One B-rep face of a CAD part: STEP entity #436.
In plain terms, the planar face has unit normal (1, 0, 0).
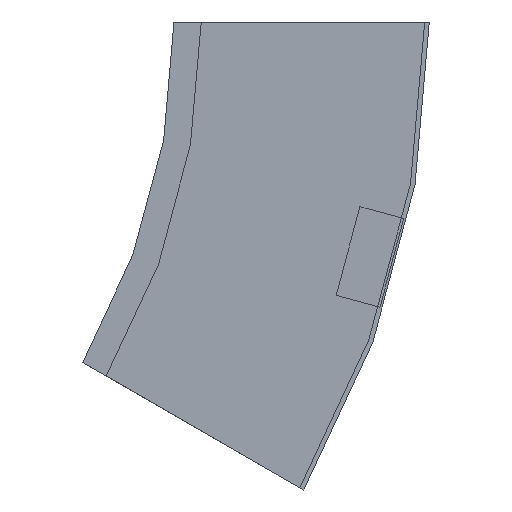
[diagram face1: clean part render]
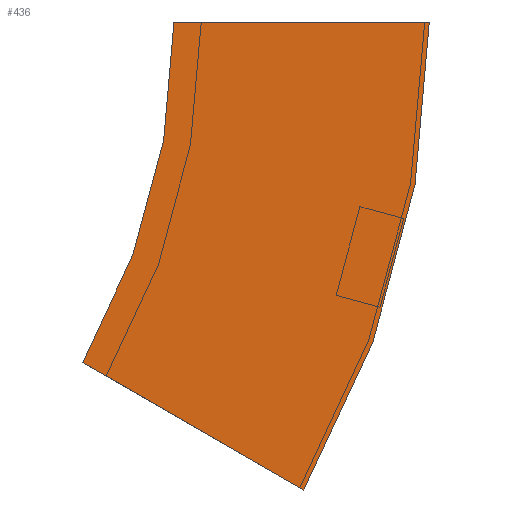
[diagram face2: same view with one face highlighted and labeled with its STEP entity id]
Its self-contained STEP definition (entity closure, numbers rounded to 3 decimals):
#1 = CARTESIAN_POINT ( 'NONE',  ( 0., -112.5, 0. ) ) ;
#70 = CARTESIAN_POINT ( 'NONE',  ( 0., -57.235, -206.25 ) ) ;
#73 = FACE_OUTER_BOUND ( 'NONE', #196, .T. ) ;
#89 = VERTEX_POINT ( 'NONE', #1 ) ;
#91 = DIRECTION ( 'NONE',  ( 1., 0., 0. ) ) ;
#94 = DIRECTION ( 'NONE',  ( 0., 1., 0. ) ) ;
#103 = CARTESIAN_POINT ( 'NONE',  ( 0., -112.5, 0. ) ) ;
#144 = AXIS2_PLACEMENT_3D ( 'NONE', #302, #219, #391 ) ;
#151 = ORIENTED_EDGE ( 'NONE', *, *, #296, .T. ) ;
#196 = EDGE_LOOP ( 'NONE', ( #497, #550, #511, #151 ) ) ;
#216 = DIRECTION ( 'NONE',  ( 0., 0., 1. ) ) ;
#219 = DIRECTION ( 'NONE',  ( 1., 0., 0. ) ) ;
#252 = PLANE ( 'NONE',  #465 ) ;
#291 = EDGE_CURVE ( 'NONE', #455, #411, #396, .T. ) ;
#296 = EDGE_CURVE ( 'NONE', #463, #411, #349, .T. ) ;
#302 = CARTESIAN_POINT ( 'NONE',  ( 0., 300., 0. ) ) ;
#315 = CARTESIAN_POINT ( 'NONE',  ( 0., -112.5, 0. ) ) ;
#319 = AXIS2_PLACEMENT_3D ( 'NONE', #482, #91, #366 ) ;
#329 = LINE ( 'NONE', #103, #480 ) ;
#349 = LINE ( 'NONE', #70, #534 ) ;
#366 = DIRECTION ( 'NONE',  ( 0., -1., 0. ) ) ;
#377 = CARTESIAN_POINT ( 'NONE',  ( 0., 40.192, -150. ) ) ;
#385 = DIRECTION ( 'NONE',  ( 0., 0.866, 0.5 ) ) ;
#388 = CARTESIAN_POINT ( 'NONE',  ( 0., 0., 0. ) ) ;
#391 = DIRECTION ( 'NONE',  ( 0., -1., 0. ) ) ;
#396 = CIRCLE ( 'NONE', #144, 300. ) ;
#400 = EDGE_CURVE ( 'NONE', #89, #463, #403, .T. ) ;
#403 = CIRCLE ( 'NONE', #319, 412.5 ) ;
#411 = VERTEX_POINT ( 'NONE', #377 ) ;
#436 = ADVANCED_FACE ( 'NONE', ( #73 ), #252, .F. ) ;
#441 = CARTESIAN_POINT ( 'NONE',  ( 0., -57.235, -206.25 ) ) ;
#455 = VERTEX_POINT ( 'NONE', #388 ) ;
#463 = VERTEX_POINT ( 'NONE', #441 ) ;
#465 = AXIS2_PLACEMENT_3D ( 'NONE', #315, #476, #216 ) ;
#476 = DIRECTION ( 'NONE',  ( -1., 0., 0. ) ) ;
#480 = VECTOR ( 'NONE', #94, 1000. ) ;
#482 = CARTESIAN_POINT ( 'NONE',  ( 0., 300., 0. ) ) ;
#497 = ORIENTED_EDGE ( 'NONE', *, *, #291, .F. ) ;
#511 = ORIENTED_EDGE ( 'NONE', *, *, #400, .T. ) ;
#534 = VECTOR ( 'NONE', #385, 1000. ) ;
#538 = EDGE_CURVE ( 'NONE', #89, #455, #329, .T. ) ;
#550 = ORIENTED_EDGE ( 'NONE', *, *, #538, .F. ) ;
